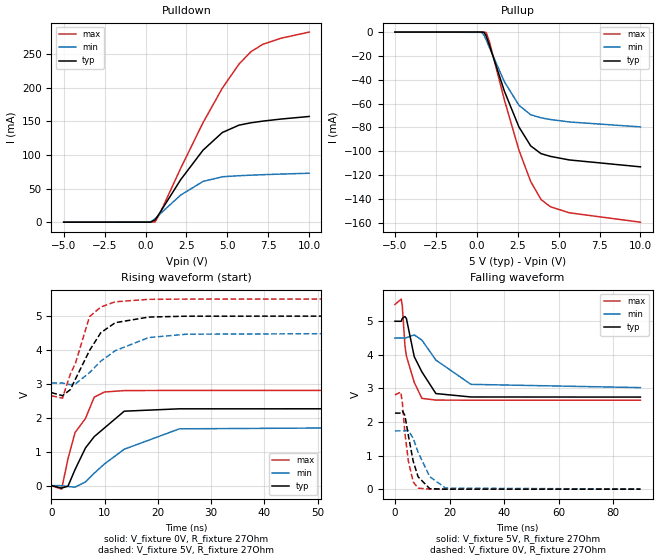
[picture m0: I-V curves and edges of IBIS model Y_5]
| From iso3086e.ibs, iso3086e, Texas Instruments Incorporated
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|   Y_5 Model
[Model]   Y_5
Model_type   3-state
|Signals   Y   positive pin
Polarity   Non-Inverting
Enable   Active-Low
Vmeas   = 2.44
Vref   = 2.5
Cref   = 50pF
|Rref = 27   |Note: 54 Ohm differential load;
| C_comp   obtained at 20MHz
|   typ   min   max
C_comp   92.18fF   92.32fF   103.5fF
[Voltage Range]   5   4.5   5.5
[Temperature Range]   40   125   -40
[Pullup Reference]   5   4.5   5.5
[Pulldown Reference]   0   0   0
[Power Clamp Reference]   5   4.5   5.5
[GND Clamp Reference]   0   0   0
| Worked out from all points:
|   slope of the pulldown table from 0 to 0.75 V, typ, clamps not added: 82.1 ohm
|   slope of the pullup table from 0 to 0.75 V, typ, clamps not added: 74 ohm
|   falling waveform, V_fixture 5V, R_fixture 27Ohm: 20-80 % time 6.1ns typ, 11ns min, 3.84ns max; typ from 5 V to 2.74 V
|   rising waveform, V_fixture 0V, R_fixture 27Ohm: 20-80 % time 6.09ns typ, 10.6ns min, 4.13ns max; typ from 0 V to 2.27 V
|   rising waveform, V_fixture 5V, R_fixture 27Ohm: 20-80 % time 4.82ns typ, 8ns min, 3.6ns max; typ from 2.74 V to 5 V
|   falling waveform, V_fixture 0V, R_fixture 27Ohm: 20-80 % time 3.53ns typ, 5.7ns min, 2.5ns max; typ from 2.27 V to 0 V
[Pulldown]
|   Voltage   I(typ)   I(min)   I(max)
-5V       -15.31fA   -85.27fA   -8.177fA
295mV     2.193uA    216.9uA    152nA
595mV     3.565mA    5.28mA     647.6uA
887.5mV   14.45mA    12.3mA     13.4mA
2.147V    63.06mA    40.21mA    79.93mA
3.513V    106.9mA    60.52mA    147.7mA
4.69V     133.1mA    67.44mA    198.9mA
5.71V     144.1mA    69mA       234.7mA
6.438V    147.6mA    69.81mA    253.1mA
7.165V    150.1mA    70.52mA    264.1mA
8.26V     153.1mA    71.44mA    273.1mA
10V       157mA      72.7mA     282.3mA
[Pullup]
|   Voltage   I(typ)   I(min)   I(max)
-5V       38.96fA    206.7fA    -596.4fA
287.5mV   -2.111uA   -192.5uA   -522.6nA
445mV     -281.1uA   -2.619mA   -1.699uA
572.5mV   -3.117mA   -6.351mA   -308.9uA
775mV     -11.18mA   -13.06mA   -8.121mA
1.69V     -49.7mA    -41.78mA   -57.09mA
2.575V    -79.63mA   -61.42mA   -99.04mA
3.295V    -95.59mA   -69.45mA   -125.5mA
3.925V    -102.1mA   -72mA      -140.6mA
4.495V    -104.4mA   -73.46mA   -146.7mA
5.65V     -107.4mA   -75.49mA   -151.8mA
10V       -113.2mA   -79.65mA   -159.7mA
[Ramp]
R_load = 27
|   typ   min   max
dV/dt_r   1.35916/6.09167e-009   1.04102/1.0666e-008   1.68401/4.12238e-009
dV/dt_f   1.35475/6.08403e-009   0.88545/1.0867e-008   1.71074/3.83626e-009
[Falling Waveform]
V_fixture = 5V
V_fixture_min = 4.5V
V_fixture_max = 5.5V
R_fixture = 27Ohm
C_fixture = 0F
|   Time   V(typ)   V(min)   V(max)
0s        5V         4.5V       5.5V
2.32ns    4.999V     4.5V       5.661V
2.72ns    5.089V     4.5V       5.434V
3.68ns    5.139V     4.499V     4.261V
4.2ns     5.082V     4.512V     3.966V
7.08ns    3.945V     4.594V     3.18V
9.88ns    3.492V     4.438V     2.703V
15ns      2.847V     3.844V     2.653V
27.84ns   2.745V     3.121V     2.649V
89.92ns   2.742V     3.024V     2.649V
[Rising Waveform]
|Vcc
V_fixture = 0V
V_fixture_min = 0V
V_fixture_max = 0V
R_fixture = 27Ohm
C_fixture = 0F
|   Time   V(typ)   V(min)   V(max)
0s        5.738nV    145.7nV    6.035nV
1.92ns    -74.96mV   -122.8uV   -105.4mV
3.12ns    -16.47mV   -28.97mV   793.6mV
4.44ns    472.4mV    -45.55mV   1.564V
6.4ns     1.11V      107.9mV    1.979V
8.04ns    1.443V     365.5mV    2.606V
9.96ns    1.699V     637.4mV    2.76V
13.68ns   2.194V     1.072V     2.801V
24.04ns   2.264V     1.673V     2.807V
89.92ns   2.265V     1.735V     2.807V
[Rising Waveform]
V_fixture = 5V
V_fixture_min = 4.5V
V_fixture_max = 5.5V
R_fixture = 27Ohm
C_fixture = 0F
|   Time   V(typ)   V(min)   V(max)
0s        2.742V     3.024V     2.649V
2.08ns    2.651V     3.024V     2.577V
3.56ns    2.83V      2.973V     3.29V
4.52ns    3.142V     2.999V     3.609V
7.16ns    3.984V     3.33V      4.982V
9.28ns    4.509V     3.67V      5.266V
12ns      4.804V     3.979V     5.42V
18.28ns   4.969V     4.365V     5.492V
25.36ns   4.995V     4.464V     5.499V
89.92ns   5V         4.5V       5.5V
[Falling Waveform]
|Gnd
V_fixture = 0V
V_fixture_min = 0V
V_fixture_max = 0V
R_fixture = 27Ohm
C_fixture = 0F
|   Time   V(typ)   V(min)   V(max)
0s        2.265V     1.735V     2.807V
2.16ns    2.264V     1.735V     2.892V
2.76ns    2.326V     1.735V     2.545V
3.64ns    2.198V     1.735V     1.678V
4.92ns    1.601V     1.744V     835.2mV
6.68ns    836.3mV    1.519V     220mV
8.48ns    369.8mV    1.099V     29.46mV
12.76ns   14.05mV    369.8mV    370.9uV
18.56ns   -147.3uV   32.31mV    114.5uV
89.92ns   52.84uV    75.65uV    40.51uV
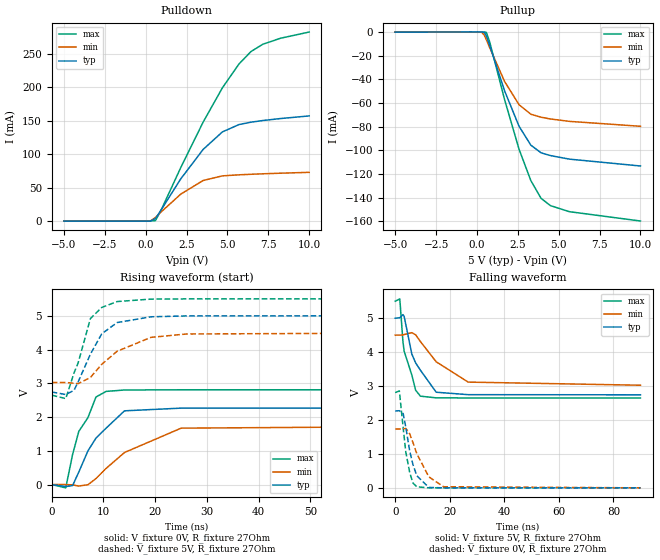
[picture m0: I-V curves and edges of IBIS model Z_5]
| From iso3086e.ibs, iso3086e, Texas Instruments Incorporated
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|   Z_5 Model
[Model]   Z_5
Model_type   3-state
|Signals   Z   negative pin
Polarity   Non-Inverting
Enable   Active-Low
Vmeas   = 2.45
Vref   = 2.5
Cref   = 50pF
|Rref = 27   |Note: 54 Ohm differential load;
| C_comp   obtained at 20MHz
|   typ   min   max
C_comp   92.18fF   92.32fF   103.5fF
[Voltage Range]   5   4.5   5.5
[Temperature Range]   40   125   -40
[Pullup Reference]   5   4.5   5.5
[Pulldown Reference]   0   0   0
[Power Clamp Reference]   5   4.5   5.5
[GND Clamp Reference]   0   0   0
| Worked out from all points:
|   slope of the pulldown table from 0 to 0.75 V, typ, clamps not added: 82.1 ohm
|   slope of the pullup table from 0 to 0.75 V, typ, clamps not added: 74 ohm
|   falling waveform, V_fixture 5V, R_fixture 27Ohm: 20-80 % time 6.36ns typ, 11.4ns min, 4.02ns max; typ from 5 V to 2.74 V
|   rising waveform, V_fixture 0V, R_fixture 27Ohm: 20-80 % time 5.76ns typ, 10.1ns min, 3.91ns max; typ from 0 V to 2.27 V
|   rising waveform, V_fixture 5V, R_fixture 27Ohm: 20-80 % time 4.61ns typ, 7.73ns min, 3.44ns max; typ from 2.74 V to 5 V
|   falling waveform, V_fixture 0V, R_fixture 27Ohm: 20-80 % time 3.62ns typ, 5.85ns min, 2.61ns max; typ from 2.27 V to 0 V
[Pulldown]
|   Voltage   I(typ)   I(min)   I(max)
-5V       -15.3fA    -85.22fA   -8.17fA
295mV     2.193uA    216.9uA    152nA
595mV     3.565mA    5.28mA     647.6uA
887.5mV   14.45mA    12.3mA     13.4mA
2.147V    63.06mA    40.21mA    79.93mA
3.513V    106.9mA    60.52mA    147.7mA
4.69V     133.1mA    67.44mA    198.9mA
5.71V     144.1mA    69mA       234.7mA
6.438V    147.6mA    69.81mA    253.1mA
7.165V    150.1mA    70.52mA    264.1mA
8.26V     153.1mA    71.44mA    273.1mA
10V       157mA      72.7mA     282.3mA
[Pullup]
|   Voltage   I(typ)   I(min)   I(max)
-5V       136.4fA    -358.3fA   -525.9fA
287.5mV   -2.111uA   -192.5uA   -522.6nA
445mV     -281.1uA   -2.619mA   -1.699uA
572.5mV   -3.117mA   -6.351mA   -308.9uA
775mV     -11.18mA   -13.06mA   -8.121mA
1.69V     -49.7mA    -41.78mA   -57.09mA
2.575V    -79.63mA   -61.42mA   -99.04mA
3.295V    -95.59mA   -69.45mA   -125.5mA
3.925V    -102.1mA   -72mA      -140.6mA
4.495V    -104.4mA   -73.46mA   -146.7mA
5.65V     -107.4mA   -75.49mA   -151.8mA
10V       -113.2mA   -79.65mA   -159.7mA
[Ramp]
R_load = 27
|   typ   min   max
dV/dt_r   1.35916/5.75839e-009   1.04102/1.01698e-008   1.68401/3.91026e-009
dV/dt_f   1.35475/6.35053e-009  0.885454/1.13161e-008   1.71074/4.00454e-009
[Falling Waveform]
V_fixture = 5V
V_fixture_min = 4.5V
V_fixture_max = 5.5V
R_fixture = 27Ohm
C_fixture = 0F
|   Time   V(typ)   V(min)   V(max)
0s        5V         4.5V       5.5V
1.68ns    5.012V     4.5V       5.569V
2.84ns    5.105V     4.504V     4.308V
3.28ns    5.053V     4.518V     4.027V
6.08ns    3.945V     4.573V     3.329V
7.48ns    3.683V     4.511V     2.879V
9.24ns    3.467V     4.311V     2.702V
15.04ns   2.818V     3.714V     2.652V
26.76ns   2.746V     3.116V     2.649V
89.92ns   2.742V     3.024V     2.649V
[Rising Waveform]
|Vcc
V_fixture = 0V
V_fixture_min = 0V
V_fixture_max = 0V
R_fixture = 27Ohm
C_fixture = 0F
|   Time   V(typ)   V(min)   V(max)
0s        5.738nV    145.7nV    6.035nV
2.72ns    -59.39mV   50.56uV    -97.17mV
4.04ns    -30.5mV    -9.278mV   891.2mV
5.24ns    371mV      -43.74mV   1.575V
7ns       995.4mV    -6.064mV   1.98V
8.56ns    1.375V     178.2mV    2.593V
10.52ns   1.671V     479.1mV    2.759V
14.08ns   2.184V     949.6mV    2.801V
25.04ns   2.264V     1.671V     2.807V
89.92ns   2.265V     1.735V     2.807V
[Rising Waveform]
V_fixture = 5V
V_fixture_min = 4.5V
V_fixture_max = 5.5V
R_fixture = 27Ohm
C_fixture = 0F
|   Time   V(typ)   V(min)   V(max)
0s        2.742V     3.024V     2.649V
2.72ns    2.666V     3.024V     2.546V
4.32ns    2.792V     3V         3.308V
5.12ns    3.043V     2.989V     3.606V
7.48ns    3.861V     3.171V     4.915V
9.68ns    4.465V     3.562V     5.246V
12.64ns   4.798V     3.947V     5.42V
19.2ns    4.969V     4.36V      5.493V
26.08ns   4.995V     4.46V      5.499V
89.92ns   5V         4.5V       5.5V
[Falling Waveform]
|Gnd
V_fixture = 0V
V_fixture_min = 0V
V_fixture_max = 0V
R_fixture = 27Ohm
C_fixture = 0F
|   Time   V(typ)   V(min)   V(max)
0s        2.265V     1.735V     2.807V
1.52ns    2.273V     1.735V     2.857V
2.92ns    2.186V     1.739V     1.766V
3.88ns    1.791V     1.752V     1.057V
5.32ns    1.081V     1.591V     448.6mV
6.52ns    682.8mV    1.332V     140.9mV
7.92ns    357.3mV    1.006V     29.87mV
12.32ns   12.53mV    326.2mV    461.2uV
17.72ns   38.25uV    32.61mV    129uV
89.92ns   52.58uV    74.96uV    40.4uV
